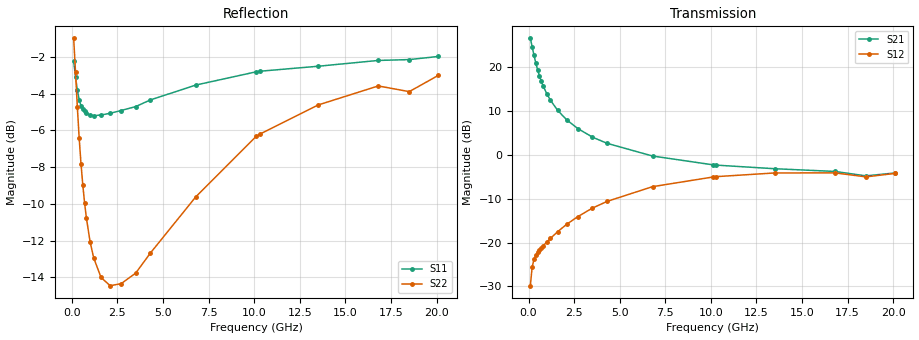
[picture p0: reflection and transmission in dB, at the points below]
!  Infineon Technologies AG
! BFR380L3 , PF131585-7, No.6, Th 09.10.01, soldered on pcb-board, measured with PP GSG850
!  Vce=1.0 V,  Ic=7.5 mA
! Common Emitter S-Parameters:  15. November 2001
#  GHz  S  MA  R  50
! f  S11  S21  S12  S22
! GHz  Mag  Ang  Mag  Ang  Mag  Ang  Mag  Ang
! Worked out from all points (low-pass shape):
!   201 points, 100 MHz to 20.1 GHz, reference 50 ohm
!   highest |S21| = 26.63 dB at 100 MHz (marker M1); lowest = -4.8 dB at 18.5 GHz (marker M2)
!   |S21| within 3 dB of the highest: start of sweep to 255.3 MHz
!   lowest |S11| = -5.2 dB at 1.2 GHz (marker M3), VSWR 3.44, Z = 14.6 - j3.56 ohm
!   |S11| at or under -10 dB: nowhere
!   |S22| runs from -14.5 to -1.0 dB; largest |S21 - S12| = 21
!   S11 on the Smith chart (normalised r, x): 100 MHz: 0.86, -2.26; 300 MHz: 0.35, -0.77; 1 GHz: 0.29, -0.13; 4.3 GHz: 0.29, +0.42; 10.3 GHz: 0.40, +1.20; 20.1 GHz: 0.95, +2.57
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0.1  0.7735 -43.0  21.46 153.4  0.03218 69.1  0.8933 -28.5
0.2  0.7017 -76.5  17.23 133.9  0.0527 55.6  0.7243 -49.6
0.3  0.6463 -100.8  13.72 121.1  0.06435 48.6  0.5812 -63.9
0.4  0.6082 -117.5  11.18 112.2  0.07165 45.1  0.4791 -74.3
0.5  0.5857 -130.0  9.328 105.6  0.07721 44.0  0.4071 -82.3
0.6  0.5726 -139.5  7.976 100.7  0.08239 43.9  0.3559 -88.7
0.7  0.5647 -147.5  6.961 96.5  0.08695 44.2  0.3175 -94.2
0.8  0.5577 -153.5  6.159 93.0  0.09171 45.0  0.2886 -99.1
1  0.552 -163.3  5.013 87.1  0.1014 46.6  0.2491 -107.3
1.2  0.55 -171.1  4.226 82.2  0.1116 48.1  0.225 -114.3
1.6  0.5521 177.1  3.228 73.8  0.1333 50.5  0.1992 -125.9
2.1  0.5583 165.9  2.51 64.9  0.1622 51.8  0.1892 -137.4
2.7  0.568 154.7  2.006 55.5  0.1976 51.6  0.1916 -149.0
3.5  0.5822 141.9  1.602 44.3  0.2472 49.3  0.2047 -160.5
4.3  0.6069 131.0  1.36 34.7  0.2949 46.0  0.232 -172.7
6.8  0.6665 102.8  0.9733 10.8  0.4348 30.9  0.3306 156.1
10.1  0.724 77.1  0.7727 -8.8  0.5599 9.7  0.4826 123.8
10.3  0.7267 75.7  0.7659 -9.6  0.5661 8.5  0.4896 121.9
13.5  0.7499 59.5  0.6969 -23.6  0.6235 -11.1  0.588 96.1
16.8  0.7777 47.5  0.6488 -34.6  0.6247 -26.7  0.6627 75.3
18.5  0.7819 45.5  0.5778 -41.4  0.5625 -35.1  0.6395 69.9
20.1  0.7975 38.3  0.6235 -45.3  0.616 -40.1  0.7083 59.4
